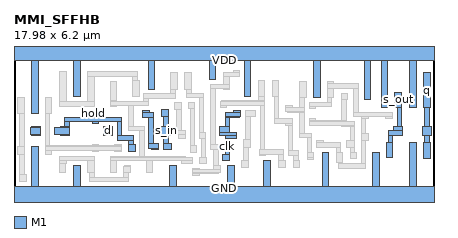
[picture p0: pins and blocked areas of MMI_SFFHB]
MACRO MMI_SFFHB
	CLASS CORE ;
	FOREIGN MMI_SFFHB 0 0 ;
	SIZE 17.98 BY 6.2 ;
	SYMMETRY X Y ;
	SITE CORE1 ;
	PIN d
		DIRECTION input ;
		USE SIGNAL ;
		PORT
			LAYER M1 ;
			RECT 3.84 2.6 4.22 2.98 ;
		END
		AntennaGateArea 0.3465 ;
	END d
	PIN GND
		DIRECTION inout ;
		USE GROUND ;
		PORT
			LAYER M1 ;
			RECT 0.75 0.42 1.03 2.105 ;
			LAYER M1 ;
			RECT 2.55 0.42 2.83 1.29 ;
			LAYER M1 ;
			RECT 6.67 0.42 6.95 1.315 ;
			LAYER M1 ;
			RECT 9.14 0.42 9.42 1.305 ;
			LAYER M1 ;
			RECT 10.7 0.42 10.98 1.5 ;
			LAYER M1 ;
			RECT 13.2 0.42 13.48 1.875 ;
			LAYER M1 ;
			RECT 15.35 0.42 15.63 1.87 ;
			LAYER M1 ;
			RECT 16.94 0.42 17.22 2.285 ;
			LAYER M1 ;
			RECT 0 -0.42 17.985 0.42 ;
		END
	END GND
	PIN q
		DIRECTION output ;
		USE SIGNAL ;
		PORT
			LAYER M1 ;
			RECT 17.53 3.8 17.81 5.27 ;
			LAYER M1 ;
			RECT 17.575 2.98 17.77 3.8 ;
			LAYER M1 ;
			RECT 17.48 2.6 17.86 2.98 ;
			LAYER M1 ;
			RECT 17.575 2.285 17.77 2.6 ;
			LAYER M1 ;
			RECT 17.53 1.585 17.81 2.285 ;
		END
		AntennaDiffArea 0.91245 ;
	END q
	PIN s_in
		DIRECTION input ;
		USE SIGNAL ;
		PORT
			LAYER M1 ;
			RECT 6.315 3.42 6.6 3.7 ;
			LAYER M1 ;
			RECT 6.405 2.98 6.6 3.42 ;
			LAYER M1 ;
			RECT 6.32 2.6 6.7 2.98 ;
			LAYER M1 ;
			RECT 6.405 2.26 6.6 2.6 ;
			LAYER M1 ;
			RECT 6.405 1.98 6.755 2.26 ;
		END
		AntennaGateArea 0.17325 ;
	END s_in
	PIN s_en
		DIRECTION input ;
		USE SIGNAL ;
		PORT
			LAYER M1 ;
			RECT 5.515 3.57 5.795 3.665 ;
			LAYER M1 ;
			RECT 5.515 3.375 5.96 3.57 ;
			LAYER M1 ;
			RECT 0.74 2.93 1.12 2.98 ;
			LAYER M1 ;
			RECT 0.7 2.65 1.12 2.93 ;
			LAYER M1 ;
			RECT 0.74 2.6 1.12 2.65 ;
			LAYER M1 ;
			RECT 5.77 2.26 5.96 3.375 ;
			LAYER M1 ;
			RECT 5.77 2.025 6.185 2.26 ;
			LAYER M1 ;
			RECT 5.905 1.98 6.185 2.025 ;
		END
		AntennaGateArea 0.9045 ;
	END s_en
	PIN VDD
		DIRECTION inout ;
		USE POWER ;
		PORT
			LAYER M1 ;
			RECT 0 5.78 17.985 6.62 ;
			LAYER M1 ;
			RECT 0.75 3.52 1.03 5.78 ;
			LAYER M1 ;
			RECT 2.55 4.25 2.83 5.78 ;
			LAYER M1 ;
			RECT 5.755 4.58 6.035 5.78 ;
			LAYER M1 ;
			RECT 8.36 4.995 8.64 5.78 ;
			LAYER M1 ;
			RECT 9.865 4.27 10.145 5.78 ;
			LAYER M1 ;
			RECT 12.825 4.22 13.105 5.78 ;
			LAYER M1 ;
			RECT 14.99 4.115 15.27 5.78 ;
			LAYER M1 ;
			RECT 15.72 3.8 16 5.78 ;
			LAYER M1 ;
			RECT 16.94 3.8 17.22 5.78 ;
		END
	END VDD
	PIN s_out
		DIRECTION output ;
		USE SIGNAL ;
		PORT
			LAYER M1 ;
			RECT 16.31 3.8 16.59 4.435 ;
			LAYER M1 ;
			RECT 16.4 2.98 16.59 3.8 ;
			LAYER M1 ;
			RECT 16.245 2.795 16.62 2.98 ;
			LAYER M1 ;
			RECT 16.025 2.6 16.62 2.795 ;
			LAYER M1 ;
			RECT 16.025 2.285 16.215 2.6 ;
			LAYER M1 ;
			RECT 15.94 1.65 16.22 2.285 ;
		END
		AntennaDiffArea 0.588675 ;
	END s_out
	PIN clk
		DIRECTION input ;
		USE CLOCK ;
		PORT
			LAYER M1 ;
			RECT 9.395 3.575 9.675 3.68 ;
			LAYER M1 ;
			RECT 9.035 3.4 9.675 3.575 ;
			LAYER M1 ;
			RECT 9.035 3.38 9.64 3.4 ;
			LAYER M1 ;
			RECT 9.035 2.98 9.225 3.38 ;
			LAYER M1 ;
			RECT 8.805 2.725 9.225 2.98 ;
			LAYER M1 ;
			RECT 8.805 2.6 9.505 2.725 ;
			LAYER M1 ;
			RECT 9.035 2.445 9.505 2.6 ;
			LAYER M1 ;
			RECT 9.035 1.785 9.225 2.445 ;
			LAYER M1 ;
			RECT 8.945 1.505 9.225 1.785 ;
		END
		AntennaGateArea 0.44625 ;
	END clk
	PIN hold
		DIRECTION input ;
		USE SIGNAL ;
		PORT
			LAYER M1 ;
			RECT 2.165 3.18 4.615 3.375 ;
			LAYER M1 ;
			RECT 2.165 2.98 2.36 3.18 ;
			LAYER M1 ;
			RECT 3.34 3.09 3.62 3.18 ;
			LAYER M1 ;
			RECT 1.98 2.925 2.36 2.98 ;
			LAYER M1 ;
			RECT 1.75 2.645 2.36 2.925 ;
			LAYER M1 ;
			RECT 1.98 2.6 2.36 2.645 ;
			LAYER M1 ;
			RECT 4.425 2.585 4.615 3.18 ;
			LAYER M1 ;
			RECT 4.425 2.39 5.095 2.585 ;
			LAYER M1 ;
			RECT 4.9 2.195 5.095 2.39 ;
			LAYER M1 ;
			RECT 4.9 1.915 5.18 2.195 ;
		END
		AntennaGateArea 0.51975 ;
	END hold
	OBS
		LAYER M1 ;
		RECT 0.16 3.52 0.44 4.22 ;
		LAYER M1 ;
		RECT 1.34 3.52 1.62 4.22 ;
		LAYER M1 ;
		RECT 1.955 4.04 2.235 5.315 ;
		LAYER M1 ;
		RECT 3.145 5.125 5.27 5.315 ;
		LAYER M1 ;
		RECT 3.145 4.04 3.435 5.125 ;
		LAYER M1 ;
		RECT 5.08 4.925 5.27 5.125 ;
		LAYER M1 ;
		RECT 1.955 3.845 3.435 4.04 ;
		LAYER M1 ;
		RECT 4.115 4.08 4.395 4.91 ;
		LAYER M1 ;
		RECT 5.08 4.255 5.36 4.925 ;
		LAYER M1 ;
		RECT 6.72 4.58 7 5.28 ;
		LAYER M1 ;
		RECT 7.31 4.58 7.59 5.28 ;
		LAYER M1 ;
		RECT 9.385 5.295 9.665 5.385 ;
		LAYER M1 ;
		RECT 8.955 5.28 9.665 5.295 ;
		LAYER M1 ;
		RECT 8.95 5.105 9.665 5.28 ;
		LAYER M1 ;
		RECT 8.95 4.78 9.23 5.105 ;
		LAYER M1 ;
		RECT 6.72 4.38 6.915 4.58 ;
		LAYER M1 ;
		RECT 5.565 4.19 6.915 4.38 ;
		LAYER M1 ;
		RECT 7.4 4.395 7.59 4.58 ;
		LAYER M1 ;
		RECT 8.415 4.59 9.23 4.78 ;
		LAYER M1 ;
		RECT 7.4 4.205 8.13 4.395 ;
		LAYER M1 ;
		RECT 4.115 4.055 4.4 4.08 ;
		LAYER M1 ;
		RECT 5.565 4.055 5.76 4.19 ;
		LAYER M1 ;
		RECT 4.115 3.865 5.76 4.055 ;
		LAYER M1 ;
		RECT 4.115 3.85 4.395 3.865 ;
		LAYER M1 ;
		RECT 0.245 2.105 0.435 3.52 ;
		LAYER M1 ;
		RECT 1.345 2.155 1.535 3.52 ;
		LAYER M1 ;
		RECT 4.91 2.98 5.105 3.865 ;
		LAYER M1 ;
		RECT 6.885 3.71 7.165 3.99 ;
		LAYER M1 ;
		RECT 7.46 3.725 7.74 4.005 ;
		LAYER M1 ;
		RECT 4.91 2.79 5.57 2.98 ;
		LAYER M1 ;
		RECT 3.355 2.155 3.635 2.195 ;
		LAYER M1 ;
		RECT 4.32 2.155 4.6 2.19 ;
		LAYER M1 ;
		RECT 1.345 2.105 4.6 2.155 ;
		LAYER M1 ;
		RECT 0.16 1.79 0.44 2.105 ;
		LAYER M1 ;
		RECT 0.245 0.905 0.435 1.79 ;
		LAYER M1 ;
		RECT 0.245 0.625 0.525 0.905 ;
		LAYER M1 ;
		RECT 1.34 1.96 4.6 2.105 ;
		LAYER M1 ;
		RECT 1.34 1.79 1.62 1.96 ;
		LAYER M1 ;
		RECT 3.355 1.915 3.635 1.96 ;
		LAYER M1 ;
		RECT 4.32 1.91 4.6 1.96 ;
		LAYER M1 ;
		RECT 5.38 1.71 5.57 2.79 ;
		LAYER M1 ;
		RECT 6.975 2.81 7.165 3.71 ;
		LAYER M1 ;
		RECT 6.975 2.62 7.325 2.81 ;
		LAYER M1 ;
		RECT 7.045 2.445 7.325 2.62 ;
		LAYER M1 ;
		RECT 7.54 2.155 7.735 3.725 ;
		LAYER M1 ;
		RECT 7.94 2.725 8.13 4.205 ;
		LAYER M1 ;
		RECT 7.935 2.445 8.215 2.725 ;
		LAYER M1 ;
		RECT 7.54 1.875 7.82 2.155 ;
		LAYER M1 ;
		RECT 1.945 1.7 2.225 1.71 ;
		LAYER M1 ;
		RECT 3.15 1.7 3.43 1.71 ;
		LAYER M1 ;
		RECT 1.945 1.51 3.435 1.7 ;
		LAYER M1 ;
		RECT 1.945 1.41 2.23 1.51 ;
		LAYER M1 ;
		RECT 1.945 1.01 2.225 1.41 ;
		LAYER M1 ;
		RECT 3.15 1.01 3.435 1.51 ;
		LAYER M1 ;
		RECT 4.12 1.66 7.34 1.71 ;
		LAYER M1 ;
		RECT 8.02 1.66 8.215 2.445 ;
		LAYER M1 ;
		RECT 8.415 2.185 8.605 4.59 ;
		LAYER M1 ;
		RECT 8.95 4.58 9.23 4.59 ;
		LAYER M1 ;
		RECT 10.46 4.245 10.74 4.945 ;
		LAYER M1 ;
		RECT 11.05 4.245 11.33 4.945 ;
		LAYER M1 ;
		RECT 10.46 4.07 10.73 4.245 ;
		LAYER M1 ;
		RECT 8.87 4.055 10.73 4.07 ;
		LAYER M1 ;
		RECT 8.825 3.885 10.73 4.055 ;
		LAYER M1 ;
		RECT 8.825 3.88 10.735 3.885 ;
		LAYER M1 ;
		RECT 8.825 3.775 9.105 3.88 ;
		LAYER M1 ;
		RECT 9.915 3.4 10.325 3.68 ;
		LAYER M1 ;
		RECT 8.415 1.995 8.745 2.185 ;
		LAYER M1 ;
		RECT 4.12 1.52 7.64 1.66 ;
		LAYER M1 ;
		RECT 4.12 1.01 4.4 1.52 ;
		LAYER M1 ;
		RECT 4.71 1.28 4.99 1.285 ;
		LAYER M1 ;
		RECT 3.245 0.81 3.435 1.01 ;
		LAYER M1 ;
		RECT 4.7 1.005 4.99 1.28 ;
		LAYER M1 ;
		RECT 4.7 0.81 4.895 1.005 ;
		LAYER M1 ;
		RECT 5.67 1 5.95 1.52 ;
		LAYER M1 ;
		RECT 7.15 1.38 7.64 1.52 ;
		LAYER M1 ;
		RECT 7.95 1.38 8.23 1.66 ;
		LAYER M1 ;
		RECT 3.245 0.62 4.895 0.81 ;
		LAYER M1 ;
		RECT 8.55 1.305 8.745 1.995 ;
		LAYER M1 ;
		RECT 9.915 2.41 10.105 3.4 ;
		LAYER M1 ;
		RECT 9.825 2.075 10.105 2.41 ;
		LAYER M1 ;
		RECT 9.825 1.5 10.02 2.075 ;
		LAYER M1 ;
		RECT 10.54 1.995 10.735 3.88 ;
		LAYER M1 ;
		RECT 11.135 3.31 11.33 4.245 ;
		LAYER M1 ;
		RECT 12.235 4.22 12.515 4.92 ;
		LAYER M1 ;
		RECT 13.415 4.815 13.695 4.92 ;
		LAYER M1 ;
		RECT 13.415 4.62 14.735 4.815 ;
		LAYER M1 ;
		RECT 13.415 4.22 13.695 4.62 ;
		LAYER M1 ;
		RECT 11.64 3.78 11.92 3.885 ;
		LAYER M1 ;
		RECT 12.235 3.78 12.43 4.22 ;
		LAYER M1 ;
		RECT 13.42 4.015 13.61 4.22 ;
		LAYER M1 ;
		RECT 14.01 4.115 14.29 4.395 ;
		LAYER M1 ;
		RECT 11.64 3.605 12.43 3.78 ;
		LAYER M1 ;
		RECT 12.63 3.825 13.61 4.015 ;
		LAYER M1 ;
		RECT 12.63 3.735 12.91 3.825 ;
		LAYER M1 ;
		RECT 11.69 3.585 12.43 3.605 ;
		LAYER M1 ;
		RECT 11.64 3.31 11.92 3.315 ;
		LAYER M1 ;
		RECT 11.135 3.115 11.925 3.31 ;
		LAYER M1 ;
		RECT 11.64 3.035 11.925 3.115 ;
		LAYER M1 ;
		RECT 10.505 1.975 10.785 1.995 ;
		LAYER M1 ;
		RECT 10.505 1.785 11.525 1.975 ;
		LAYER M1 ;
		RECT 10.505 1.715 10.785 1.785 ;
		LAYER M1 ;
		RECT 11.33 1.535 11.525 1.785 ;
		LAYER M1 ;
		RECT 11.73 1.93 11.925 3.035 ;
		LAYER M1 ;
		RECT 12.235 2.68 12.43 3.585 ;
		LAYER M1 ;
		RECT 12.63 3.22 12.91 3.315 ;
		LAYER M1 ;
		RECT 14.035 3.22 14.23 4.115 ;
		LAYER M1 ;
		RECT 14.545 3.595 14.735 4.62 ;
		LAYER M1 ;
		RECT 14.545 3.4 16.195 3.595 ;
		LAYER M1 ;
		RECT 12.63 3.18 14.23 3.22 ;
		LAYER M1 ;
		RECT 14.875 3.31 15.16 3.4 ;
		LAYER M1 ;
		RECT 15.915 3.315 16.195 3.4 ;
		LAYER M1 ;
		RECT 12.63 3.035 14.595 3.18 ;
		LAYER M1 ;
		RECT 12.68 3.025 14.595 3.035 ;
		LAYER M1 ;
		RECT 14.035 2.985 14.595 3.025 ;
		LAYER M1 ;
		RECT 12.235 2.49 12.745 2.68 ;
		LAYER M1 ;
		RECT 11.73 1.74 12.16 1.93 ;
		LAYER M1 ;
		RECT 7.655 1.15 7.935 1.16 ;
		LAYER M1 ;
		RECT 8.55 1.15 8.83 1.305 ;
		LAYER M1 ;
		RECT 7.655 0.99 8.83 1.15 ;
		LAYER M1 ;
		RECT 7.655 0.955 8.745 0.99 ;
		LAYER M1 ;
		RECT 7.655 0.88 7.935 0.955 ;
		LAYER M1 ;
		RECT 9.74 1.22 10.02 1.5 ;
		LAYER M1 ;
		RECT 11.33 1.22 11.61 1.535 ;
		LAYER M1 ;
		RECT 11.965 1.505 12.16 1.74 ;
		LAYER M1 ;
		RECT 12.555 1.875 12.745 2.49 ;
		LAYER M1 ;
		RECT 14.4 2.355 14.595 2.985 ;
		LAYER M1 ;
		RECT 12.955 2.27 13.235 2.355 ;
		LAYER M1 ;
		RECT 12.955 2.08 13.985 2.27 ;
		LAYER M1 ;
		RECT 12.955 2.075 13.235 2.08 ;
		LAYER M1 ;
		RECT 13.795 1.875 13.985 2.08 ;
		LAYER M1 ;
		RECT 14.215 2.075 14.595 2.355 ;
		LAYER M1 ;
		RECT 12.555 1.665 12.84 1.875 ;
		LAYER M1 ;
		RECT 12.56 1.56 12.84 1.665 ;
		LAYER M1 ;
		RECT 11.96 1.225 12.24 1.505 ;
		LAYER M1 ;
		RECT 13.79 1.425 14.07 1.875 ;
		LAYER M1 ;
		RECT 14.4 1.87 14.595 2.075 ;
		LAYER M1 ;
		RECT 14.875 2.66 15.065 3.31 ;
		LAYER M1 ;
		RECT 14.875 2.38 15.155 2.66 ;
		LAYER M1 ;
		RECT 14.39 1.59 14.67 1.87 ;
		LAYER M1 ;
		RECT 13.875 1.385 14.07 1.425 ;
		LAYER M1 ;
		RECT 14.875 1.385 15.065 2.38 ;
		LAYER M1 ;
		RECT 13.875 1.195 15.065 1.385 ;
	END
END MMI_SFFHB
